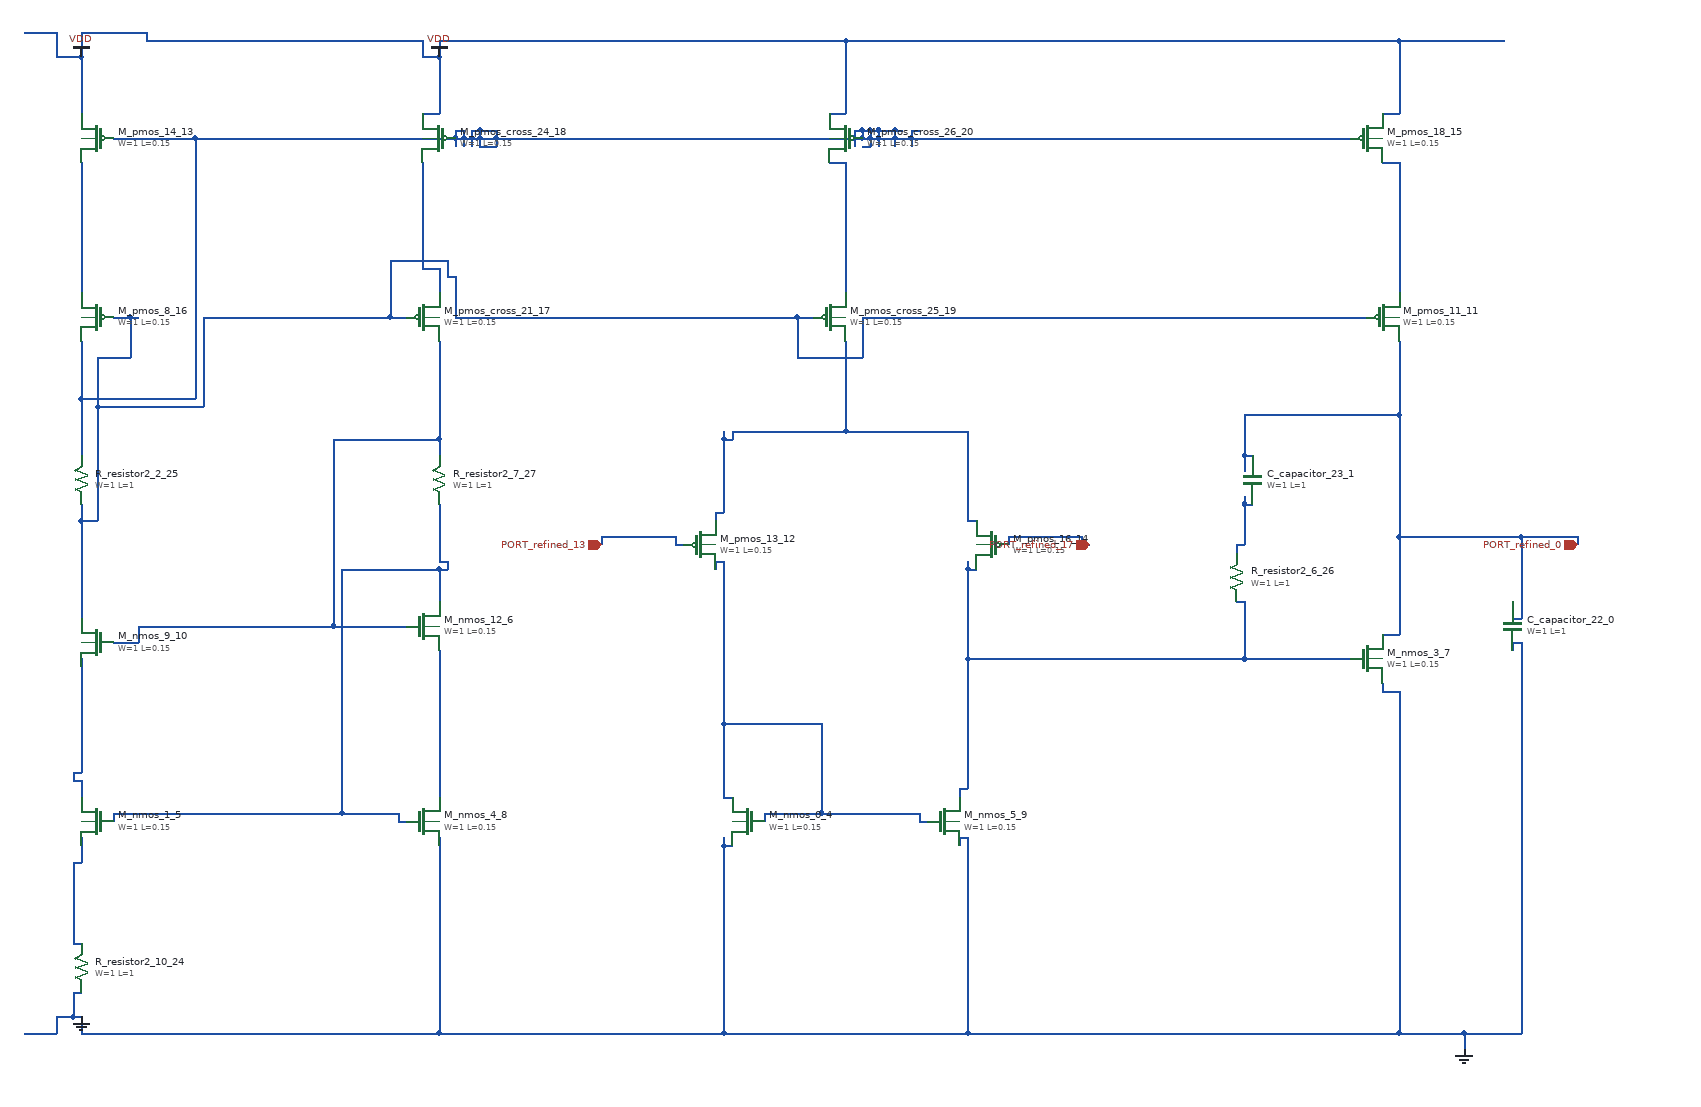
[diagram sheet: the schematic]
v {xschem version=3.4.8 file_version=1.2}
G {}
K {}
V {}
S {}
E {}
C {sky130_fd_pr/cap_mim_m3_1.sym} 1840 780 2 0 {name="C_capacitor_22_0" model=cap_mim_m3_1 W=1 L=1 MF=1 spiceprefix=X}
C {sky130_fd_pr/cap_mim_m3_1.sym} 1520 600 2 0 {name="C_capacitor_23_1" model=cap_mim_m3_1 W=1 L=1 MF=1 spiceprefix=X}
C {devices/gnd.sym} 1780 1300 0 0 {name="l_gnd_15_2" lab="GND"}
C {devices/gnd.sym} 80 1260 0 0 {name="l_gnd_31_3" lab="GND"}
C {sky130_fd_pr/nfet3_01v8.sym} 900 1020 0 1 {name="M_nmos_0_4"
W=1
L=0.15
body=GND
nf=1
mult=1
ad="expr('int((@nf + 1)/2) * @W / @nf * 0.29')"
pd="expr('2*int((@nf + 1)/2) * (@W / @nf + 0.29)')"
as="expr('int((@nf + 2)/2) * @W / @nf * 0.29')"
ps="expr('2*int((@nf + 2)/2) * (@W / @nf + 0.29)')"
nrd="expr('0.29 / @W ')" nrs="expr('0.29 / @W ')"
sa=0 sb=0 sd=0
model=nfet_01v8
spiceprefix=X
}
C {sky130_fd_pr/nfet3_01v8.sym} 100 1020 0 1 {name="M_nmos_1_5"
W=1
L=0.15
body=GND
nf=1
mult=1
ad="expr('int((@nf + 1)/2) * @W / @nf * 0.29')"
pd="expr('2*int((@nf + 1)/2) * (@W / @nf + 0.29)')"
as="expr('int((@nf + 2)/2) * @W / @nf * 0.29')"
ps="expr('2*int((@nf + 2)/2) * (@W / @nf + 0.29)')"
nrd="expr('0.29 / @W ')" nrs="expr('0.29 / @W ')"
sa=0 sb=0 sd=0
model=nfet_01v8
spiceprefix=X
}
C {sky130_fd_pr/nfet3_01v8.sym} 500 780 0 0 {name="M_nmos_12_6"
W=1
L=0.15
body=GND
nf=1
mult=1
ad="expr('int((@nf + 1)/2) * @W / @nf * 0.29')"
pd="expr('2*int((@nf + 1)/2) * (@W / @nf + 0.29)')"
as="expr('int((@nf + 2)/2) * @W / @nf * 0.29')"
ps="expr('2*int((@nf + 2)/2) * (@W / @nf + 0.29)')"
nrd="expr('0.29 / @W ')" nrs="expr('0.29 / @W ')"
sa=0 sb=0 sd=0
model=nfet_01v8
spiceprefix=X
}
C {sky130_fd_pr/nfet3_01v8.sym} 1660 820 0 0 {name="M_nmos_3_7"
W=1
L=0.15
body=GND
nf=1
mult=1
ad="expr('int((@nf + 1)/2) * @W / @nf * 0.29')"
pd="expr('2*int((@nf + 1)/2) * (@W / @nf + 0.29)')"
as="expr('int((@nf + 2)/2) * @W / @nf * 0.29')"
ps="expr('2*int((@nf + 2)/2) * (@W / @nf + 0.29)')"
nrd="expr('0.29 / @W ')" nrs="expr('0.29 / @W ')"
sa=0 sb=0 sd=0
model=nfet_01v8
spiceprefix=X
}
C {sky130_fd_pr/nfet3_01v8.sym} 500 1020 0 0 {name="M_nmos_4_8"
W=1
L=0.15
body=GND
nf=1
mult=1
ad="expr('int((@nf + 1)/2) * @W / @nf * 0.29')"
pd="expr('2*int((@nf + 1)/2) * (@W / @nf + 0.29)')"
as="expr('int((@nf + 2)/2) * @W / @nf * 0.29')"
ps="expr('2*int((@nf + 2)/2) * (@W / @nf + 0.29)')"
nrd="expr('0.29 / @W ')" nrs="expr('0.29 / @W ')"
sa=0 sb=0 sd=0
model=nfet_01v8
spiceprefix=X
}
C {sky130_fd_pr/nfet3_01v8.sym} 1140 1020 0 0 {name="M_nmos_5_9"
W=1
L=0.15
body=GND
nf=1
mult=1
ad="expr('int((@nf + 1)/2) * @W / @nf * 0.29')"
pd="expr('2*int((@nf + 1)/2) * (@W / @nf + 0.29)')"
as="expr('int((@nf + 2)/2) * @W / @nf * 0.29')"
ps="expr('2*int((@nf + 2)/2) * (@W / @nf + 0.29)')"
nrd="expr('0.29 / @W ')" nrs="expr('0.29 / @W ')"
sa=0 sb=0 sd=0
model=nfet_01v8
spiceprefix=X
}
C {sky130_fd_pr/nfet3_01v8.sym} 100 800 0 1 {name="M_nmos_9_10"
W=1
L=0.15
body=GND
nf=1
mult=1
ad="expr('int((@nf + 1)/2) * @W / @nf * 0.29')"
pd="expr('2*int((@nf + 1)/2) * (@W / @nf + 0.29)')"
as="expr('int((@nf + 2)/2) * @W / @nf * 0.29')"
ps="expr('2*int((@nf + 2)/2) * (@W / @nf + 0.29)')"
nrd="expr('0.29 / @W ')" nrs="expr('0.29 / @W ')"
sa=0 sb=0 sd=0
model=nfet_01v8
spiceprefix=X
}
C {sky130_fd_pr/pfet3_01v8.sym} 1680 400 0 0 {name="M_pmos_11_11"
W=1
L=0.15
body=VDD
nf=1
mult=1
ad="expr('int((@nf + 1)/2) * @W / @nf * 0.29')"
pd="expr('2*int((@nf + 1)/2) * (@W / @nf + 0.29)')"
as="expr('int((@nf + 2)/2) * @W / @nf * 0.29')"
ps="expr('2*int((@nf + 2)/2) * (@W / @nf + 0.29)')"
nrd="expr('0.29 / @W ')" nrs="expr('0.29 / @W ')"
sa=0 sb=0 sd=0
model=pfet_01v8
spiceprefix=X
}
C {sky130_fd_pr/pfet3_01v8.sym} 840 680 0 0 {name="M_pmos_13_12"
W=1
L=0.15
body=VDD
nf=1
mult=1
ad="expr('int((@nf + 1)/2) * @W / @nf * 0.29')"
pd="expr('2*int((@nf + 1)/2) * (@W / @nf + 0.29)')"
as="expr('int((@nf + 2)/2) * @W / @nf * 0.29')"
ps="expr('2*int((@nf + 2)/2) * (@W / @nf + 0.29)')"
nrd="expr('0.29 / @W ')" nrs="expr('0.29 / @W ')"
sa=0 sb=0 sd=0
model=pfet_01v8
spiceprefix=X
}
C {sky130_fd_pr/pfet3_01v8.sym} 100 180 0 1 {name="M_pmos_14_13"
W=1
L=0.15
body=VDD
nf=1
mult=1
ad="expr('int((@nf + 1)/2) * @W / @nf * 0.29')"
pd="expr('2*int((@nf + 1)/2) * (@W / @nf + 0.29)')"
as="expr('int((@nf + 2)/2) * @W / @nf * 0.29')"
ps="expr('2*int((@nf + 2)/2) * (@W / @nf + 0.29)')"
nrd="expr('0.29 / @W ')" nrs="expr('0.29 / @W ')"
sa=0 sb=0 sd=0
model=pfet_01v8
spiceprefix=X
}
C {sky130_fd_pr/pfet3_01v8.sym} 1200 680 0 1 {name="M_pmos_16_14"
W=1
L=0.15
body=VDD
nf=1
mult=1
ad="expr('int((@nf + 1)/2) * @W / @nf * 0.29')"
pd="expr('2*int((@nf + 1)/2) * (@W / @nf + 0.29)')"
as="expr('int((@nf + 2)/2) * @W / @nf * 0.29')"
ps="expr('2*int((@nf + 2)/2) * (@W / @nf + 0.29)')"
nrd="expr('0.29 / @W ')" nrs="expr('0.29 / @W ')"
sa=0 sb=0 sd=0
model=pfet_01v8
spiceprefix=X
}
C {sky130_fd_pr/pfet3_01v8.sym} 1660 180 0 0 {name="M_pmos_18_15"
W=1
L=0.15
body=VDD
nf=1
mult=1
ad="expr('int((@nf + 1)/2) * @W / @nf * 0.29')"
pd="expr('2*int((@nf + 1)/2) * (@W / @nf + 0.29)')"
as="expr('int((@nf + 2)/2) * @W / @nf * 0.29')"
ps="expr('2*int((@nf + 2)/2) * (@W / @nf + 0.29)')"
nrd="expr('0.29 / @W ')" nrs="expr('0.29 / @W ')"
sa=0 sb=0 sd=0
model=pfet_01v8
spiceprefix=X
}
C {sky130_fd_pr/pfet3_01v8.sym} 100 400 0 1 {name="M_pmos_8_16"
W=1
L=0.15
body=VDD
nf=1
mult=1
ad="expr('int((@nf + 1)/2) * @W / @nf * 0.29')"
pd="expr('2*int((@nf + 1)/2) * (@W / @nf + 0.29)')"
as="expr('int((@nf + 2)/2) * @W / @nf * 0.29')"
ps="expr('2*int((@nf + 2)/2) * (@W / @nf + 0.29)')"
nrd="expr('0.29 / @W ')" nrs="expr('0.29 / @W ')"
sa=0 sb=0 sd=0
model=pfet_01v8
spiceprefix=X
}
C {sky130_fd_pr/pfet3_01v8.sym} 500 400 0 0 {name="M_pmos_cross_21_17"
W=1
L=0.15
body=VDD
nf=1
mult=1
ad="expr('int((@nf + 1)/2) * @W / @nf * 0.29')"
pd="expr('2*int((@nf + 1)/2) * (@W / @nf + 0.29)')"
as="expr('int((@nf + 2)/2) * @W / @nf * 0.29')"
ps="expr('2*int((@nf + 2)/2) * (@W / @nf + 0.29)')"
nrd="expr('0.29 / @W ')" nrs="expr('0.29 / @W ')"
sa=0 sb=0 sd=0
model=pfet_01v8
spiceprefix=X
}
C {sky130_fd_pr/pfet3_01v8.sym} 520 180 0 1 {name="M_pmos_cross_24_18"
W=1
L=0.15
body=VDD
nf=1
mult=1
ad="expr('int((@nf + 1)/2) * @W / @nf * 0.29')"
pd="expr('2*int((@nf + 1)/2) * (@W / @nf + 0.29)')"
as="expr('int((@nf + 2)/2) * @W / @nf * 0.29')"
ps="expr('2*int((@nf + 2)/2) * (@W / @nf + 0.29)')"
nrd="expr('0.29 / @W ')" nrs="expr('0.29 / @W ')"
sa=0 sb=0 sd=0
model=pfet_01v8
spiceprefix=X
}
C {sky130_fd_pr/pfet3_01v8.sym} 1000 400 0 0 {name="M_pmos_cross_25_19"
W=1
L=0.15
body=VDD
nf=1
mult=1
ad="expr('int((@nf + 1)/2) * @W / @nf * 0.29')"
pd="expr('2*int((@nf + 1)/2) * (@W / @nf + 0.29)')"
as="expr('int((@nf + 2)/2) * @W / @nf * 0.29')"
ps="expr('2*int((@nf + 2)/2) * (@W / @nf + 0.29)')"
nrd="expr('0.29 / @W ')" nrs="expr('0.29 / @W ')"
sa=0 sb=0 sd=0
model=pfet_01v8
spiceprefix=X
}
C {sky130_fd_pr/pfet3_01v8.sym} 1020 180 0 1 {name="M_pmos_cross_26_20"
W=1
L=0.15
body=VDD
nf=1
mult=1
ad="expr('int((@nf + 1)/2) * @W / @nf * 0.29')"
pd="expr('2*int((@nf + 1)/2) * (@W / @nf + 0.29)')"
as="expr('int((@nf + 2)/2) * @W / @nf * 0.29')"
ps="expr('2*int((@nf + 2)/2) * (@W / @nf + 0.29)')"
nrd="expr('0.29 / @W ')" nrs="expr('0.29 / @W ')"
sa=0 sb=0 sd=0
model=pfet_01v8
spiceprefix=X
}
C {devices/ipin.sym} 1920 680 0 0 {name="p_port_17_21" lab="PORT_refined_0"}
C {devices/ipin.sym} 720 680 0 0 {name="p_port_19_22" lab="PORT_refined_13"}
C {devices/ipin.sym} 1320 680 0 0 {name="p_port_20_23" lab="PORT_refined_17"}
C {sky130_fd_pr/res_generic_po.sym} 80 1200 2 0 {name="R_resistor2_10_24"
W=1
L=1
model=res_generic_po
spiceprefix=X
mult=1}
C {sky130_fd_pr/res_generic_po.sym} 80 600 2 0 {name="R_resistor2_2_25"
W=1
L=1
model=res_generic_po
spiceprefix=X
mult=1}
C {sky130_fd_pr/res_generic_po.sym} 1500 720 2 0 {name="R_resistor2_6_26"
W=1
L=1
model=res_generic_po
spiceprefix=X
mult=1}
C {sky130_fd_pr/res_generic_po.sym} 520 600 2 0 {name="R_resistor2_7_27"
W=1
L=1
model=res_generic_po
spiceprefix=X
mult=1}
C {devices/vdd.sym} 80 80 0 0 {name="l_vdd_29_28" lab="VDD"}
C {devices/vdd.sym} 520 80 0 0 {name="l_vdd_30_29" lab="VDD"}
N 1680 790 1700 790 {}
N 1840 770 1850 770 {}
N 1700 670 1850 670 {}
N 1850 670 1920 670 {}
N 1510 570 1520 570 {}
N 1510 520 1700 520 {}
N 1510 590 1510 570 {}
N 1510 570 1510 520 {}
N 1700 790 1700 670 {}
N 1700 670 1700 520 {}
N 1700 520 1700 430 {}
N 1840 770 1840 750 {}
N 1850 770 1850 670 {}
N 1920 680 1920 670 {}
N 10 1280 50 1280 {}
N 80 1280 520 1280 {}
N 520 1280 870 1280 {}
N 870 1280 1170 1280 {}
N 1170 1280 1700 1280 {}
N 1700 1280 1780 1280 {}
N 1780 1280 1850 1280 {}
N 50 1260 70 1260 {}
N 70 1260 80 1260 {}
N 70 1230 80 1230 {}
N 870 1050 880 1050 {}
N 1160 1040 1170 1040 {}
N 1680 860 1700 860 {}
N 1840 800 1850 800 {}
N 50 1280 50 1260 {}
N 70 1260 70 1230 {}
N 80 1280 80 1260 {}
N 520 1280 520 1050 {}
N 520 1050 520 1040 {}
N 870 1280 870 1050 {}
N 870 1050 870 1040 {}
N 1160 1050 1160 1040 {}
N 1170 1280 1170 1040 {}
N 1680 860 1680 850 {}
N 1700 1280 1700 860 {}
N 1780 1300 1780 1280 {}
N 1840 810 1840 800 {}
N 1850 1280 1850 800 {}
N 1500 680 1510 680 {}
N 1510 630 1520 630 {}
N 1500 690 1500 680 {}
N 1510 680 1510 630 {}
N 1510 630 1510 620 {}
N 1680 210 1700 210 {}
N 1700 370 1700 210 {}
N 1170 650 1180 650 {}
N 860 640 870 640 {}
N 870 550 880 550 {}
N 880 540 1020 540 {}
N 1020 540 1170 540 {}
N 860 650 860 640 {}
N 870 640 870 550 {}
N 870 550 870 540 {}
N 880 550 880 540 {}
N 1020 540 1020 430 {}
N 1170 650 1170 540 {}
N 810 680 820 680 {}
N 720 670 810 670 {}
N 720 680 720 670 {}
N 810 680 810 670 {}
N 80 380 80 370 {}
N 80 370 80 210 {}
N 500 150 520 150 {}
N 1000 150 1020 150 {}
N 1680 150 1700 150 {}
N 50 80 80 80 {}
N 500 80 520 80 {}
N 160 60 500 60 {}
N 520 60 1020 60 {}
N 1020 60 1700 60 {}
N 1700 60 1830 60 {}
N 10 50 50 50 {}
N 80 50 160 50 {}
N 50 80 50 50 {}
N 80 150 80 80 {}
N 80 80 80 50 {}
N 160 60 160 50 {}
N 500 80 500 60 {}
N 520 150 520 80 {}
N 520 80 520 60 {}
N 1020 150 1020 60 {}
N 1700 150 1700 60 {}
N 80 500 220 500 {}
N 570 190 590 190 {}
N 1040 190 1050 190 {}
N 120 180 220 180 {}
N 220 180 540 180 {}
N 540 180 550 180 {}
N 550 180 560 180 {}
N 560 180 570 180 {}
N 570 180 590 180 {}
N 590 180 1030 180 {}
N 1030 180 1040 180 {}
N 1040 180 1050 180 {}
N 1050 180 1060 180 {}
N 1060 180 1080 180 {}
N 1080 180 1100 180 {}
N 1100 180 1640 180 {}
N 540 170 550 170 {}
N 560 170 570 170 {}
N 570 170 590 170 {}
N 1030 170 1040 170 {}
N 1040 170 1050 170 {}
N 1050 170 1060 170 {}
N 1060 170 1080 170 {}
N 1080 170 1090 170 {}
N 1100 170 1110 170 {}
N 80 570 80 500 {}
N 80 500 80 430 {}
N 220 500 220 180 {}
N 540 190 540 180 {}
N 540 180 540 170 {}
N 550 190 550 180 {}
N 550 180 550 170 {}
N 560 190 560 180 {}
N 560 180 560 170 {}
N 570 190 570 180 {}
N 570 180 570 170 {}
N 590 190 590 180 {}
N 590 180 590 170 {}
N 1030 190 1030 180 {}
N 1030 180 1030 170 {}
N 1040 180 1040 170 {}
N 1050 190 1050 180 {}
N 1050 180 1050 170 {}
N 1060 190 1060 180 {}
N 1060 180 1060 170 {}
N 1080 190 1080 180 {}
N 1080 180 1080 170 {}
N 1100 190 1100 180 {}
N 1100 180 1100 170 {}
N 1310 680 1320 680 {}
N 1220 670 1310 670 {}
N 1220 680 1220 670 {}
N 1310 680 1310 670 {}
N 1000 210 1020 210 {}
N 1020 380 1020 370 {}
N 1020 370 1020 210 {}
N 70 1170 80 1170 {}
N 70 1070 80 1070 {}
N 70 1170 70 1070 {}
N 80 1070 80 1050 {}
N 80 1050 80 1040 {}
N 70 970 80 970 {}
N 70 960 80 960 {}
N 70 970 70 960 {}
N 80 990 80 970 {}
N 80 960 80 830 {}
N 80 830 80 820 {}
N 470 1020 480 1020 {}
N 120 1010 400 1010 {}
N 400 1010 470 1010 {}
N 400 710 520 710 {}
N 520 710 530 710 {}
N 520 700 530 700 {}
N 120 1020 120 1010 {}
N 400 1010 400 710 {}
N 470 1020 470 1010 {}
N 520 750 520 710 {}
N 520 700 520 630 {}
N 530 710 530 700 {}
N 520 990 520 810 {}
N 120 800 150 800 {}
N 150 780 390 780 {}
N 390 780 480 780 {}
N 390 550 520 550 {}
N 150 800 150 780 {}
N 390 780 390 550 {}
N 520 570 520 550 {}
N 520 550 520 430 {}
N 1160 980 1170 980 {}
N 1170 820 1510 820 {}
N 1510 820 1640 820 {}
N 1500 750 1510 750 {}
N 1170 710 1180 710 {}
N 1160 990 1160 980 {}
N 1170 980 1170 820 {}
N 1170 820 1170 710 {}
N 1170 710 1170 700 {}
N 1510 820 1510 750 {}
N 1110 1020 1120 1020 {}
N 920 1010 990 1010 {}
N 990 1010 1110 1010 {}
N 870 990 880 990 {}
N 870 900 990 900 {}
N 860 700 870 700 {}
N 860 710 860 700 {}
N 870 990 870 900 {}
N 870 900 870 700 {}
N 920 1020 920 1010 {}
N 990 1010 990 900 {}
N 1110 1020 1110 1010 {}
N 80 650 100 650 {}
N 100 510 230 510 {}
N 100 450 140 450 {}
N 960 450 1040 450 {}
N 120 400 140 400 {}
N 140 400 150 400 {}
N 230 400 460 400 {}
N 460 400 480 400 {}
N 540 400 960 400 {}
N 960 400 980 400 {}
N 1040 400 1660 400 {}
N 530 350 540 350 {}
N 460 330 530 330 {}
N 80 770 80 650 {}
N 80 650 80 630 {}
N 100 650 100 510 {}
N 100 510 100 450 {}
N 140 450 140 400 {}
N 230 510 230 400 {}
N 460 400 460 330 {}
N 530 350 530 330 {}
N 540 400 540 350 {}
N 960 450 960 400 {}
N 1040 450 1040 400 {}
N 500 340 520 340 {}
N 500 340 500 210 {}
N 520 370 520 340 {}
